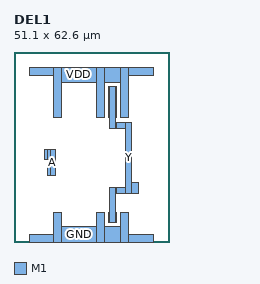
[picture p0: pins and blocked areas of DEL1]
MACRO DEL1
  CLASS CORE ;
  ORIGIN 0 0 ;
  SIZE 51.100 BY 62.600 ;
  SYMMETRY X Y ;
  SITE TR1um_site ;
  PIN Y
    DIRECTION OUTPUT ;
    USE SIGNAL ;
    PORT
      LAYER M1 ;
        RECT 31.100 6.400 31.500 9.800 ;
      LAYER M1 ;
        RECT 31.100 41.000 31.500 51.200 ;
      LAYER M1 ;
        RECT 31.500 6.400 33.300 17.900 ;
      LAYER M1 ;
        RECT 31.500 37.500 33.300 51.200 ;
      LAYER M1 ;
        RECT 33.300 6.400 33.700 9.800 ;
      LAYER M1 ;
        RECT 33.300 16.100 33.700 17.900 ;
      LAYER M1 ;
        RECT 33.300 37.500 33.700 39.300 ;
      LAYER M1 ;
        RECT 33.300 41.000 33.700 51.200 ;
      LAYER M1 ;
        RECT 33.700 16.100 36.900 17.900 ;
      LAYER M1 ;
        RECT 33.700 37.500 36.900 39.300 ;
      LAYER M1 ;
        RECT 36.900 16.100 38.700 39.300 ;
      LAYER M1 ;
        RECT 38.700 16.100 41.000 19.500 ;
    END
  END Y
  PIN A
    DIRECTION INPUT ;
    USE SIGNAL ;
    PORT
      LAYER M1 ;
        RECT 10.100 27.100 11.100 30.500 ;
      LAYER M1 ;
        RECT 11.100 22.000 11.900 24.600 ;
      LAYER M1 ;
        RECT 11.100 27.100 11.900 30.500 ;
      LAYER M1 ;
        RECT 11.900 22.000 13.700 30.500 ;
    END
  END A
  PIN VDD
    DIRECTION INOUT ;
    USE POWER ;
    PORT
      LAYER M1 ;
        RECT 5.000 55.000 13.100 57.600 ;
      LAYER M1 ;
        RECT 13.100 41.000 15.700 57.600 ;
      LAYER M1 ;
        RECT 15.700 52.600 27.100 57.600 ;
      LAYER M1 ;
        RECT 27.100 41.000 29.700 57.600 ;
      LAYER M1 ;
        RECT 29.700 52.600 35.100 57.600 ;
      LAYER M1 ;
        RECT 35.100 41.000 37.700 57.600 ;
      LAYER M1 ;
        RECT 37.700 55.000 46.100 57.600 ;
    END
  END VDD
  PIN GND
    DIRECTION INOUT ;
    USE GROUND ;
    PORT
      LAYER M1 ;
        RECT 5.000 0.000 13.100 2.600 ;
      LAYER M1 ;
        RECT 13.100 0.000 15.700 9.800 ;
      LAYER M1 ;
        RECT 15.700 0.000 27.100 5.000 ;
      LAYER M1 ;
        RECT 27.100 0.000 29.700 9.800 ;
      LAYER M1 ;
        RECT 29.700 0.000 35.100 5.000 ;
      LAYER M1 ;
        RECT 35.100 0.000 37.700 9.800 ;
      LAYER M1 ;
        RECT 37.700 0.000 46.100 2.600 ;
    END
  END GND
END DEL1
